VERSION 5.8 ;
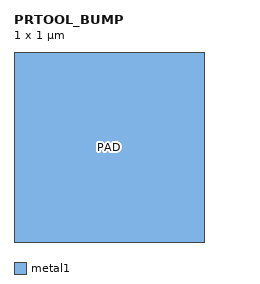
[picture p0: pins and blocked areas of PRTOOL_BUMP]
MACRO PRTOOL_BUMP
  CLASS COVER BUMP ;
  ORIGIN 0 0 ;
  SIZE 1 BY 1 ;
  PIN PAD
    DIRECTION INOUT ;
    USE SIGNAL ;
    PORT
      LAYER metal1 ;
        RECT 0 0 1 1 ;
    END
  END PAD
END PRTOOL_BUMP
END LIBRARY
